One B-rep face of a CAD part: STEP entity #131.
In plain terms, the planar face has unit normal (0, 0, 1).
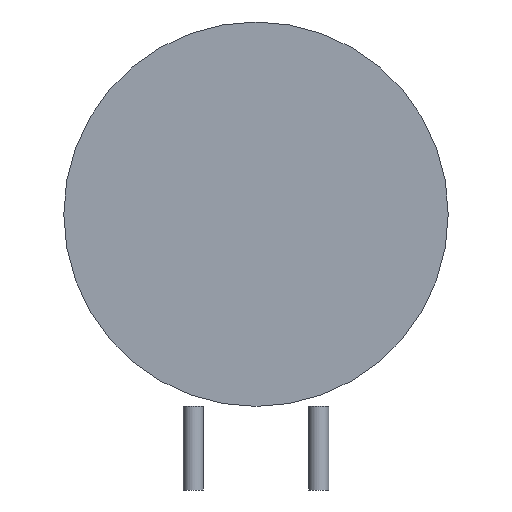
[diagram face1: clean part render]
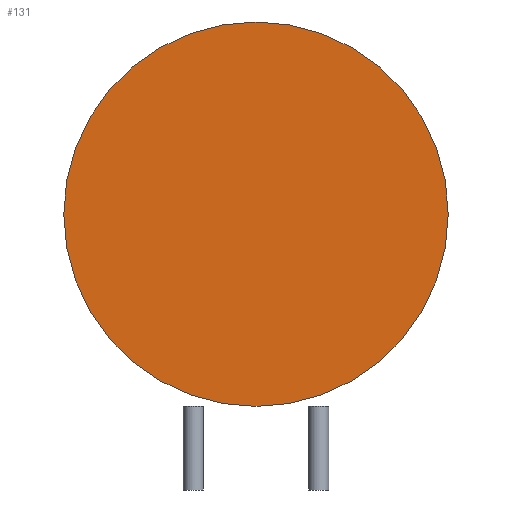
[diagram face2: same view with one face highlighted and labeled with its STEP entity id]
Its self-contained STEP definition (entity closure, numbers rounded to 3 decimals):
#47 = EDGE_CURVE('',#48,#48,#50,.T.);
#48 = VERTEX_POINT('',#49);
#49 = CARTESIAN_POINT('',(11.5,0.,9.));
#50 = SURFACE_CURVE('',#51,(#56,#68),.PCURVE_S1.);
#51 = CIRCLE('',#52,11.5);
#52 = AXIS2_PLACEMENT_3D('',#53,#54,#55);
#53 = CARTESIAN_POINT('',(0.,0.,9.));
#54 = DIRECTION('',(0.,0.,1.));
#55 = DIRECTION('',(1.,0.,-0.));
#56 = PCURVE('',#57,#62);
#57 = CYLINDRICAL_SURFACE('',#58,11.5);
#58 = AXIS2_PLACEMENT_3D('',#59,#60,#61);
#59 = CARTESIAN_POINT('',(0.,0.,0.));
#60 = DIRECTION('',(0.,0.,1.));
#61 = DIRECTION('',(1.,0.,-0.));
#62 = DEFINITIONAL_REPRESENTATION('',(#63),#67);
#63 = LINE('',#64,#65);
#64 = CARTESIAN_POINT('',(0.,9.));
#65 = VECTOR('',#66,1.);
#66 = DIRECTION('',(1.,0.));
#67 = ( GEOMETRIC_REPRESENTATION_CONTEXT(2) 
PARAMETRIC_REPRESENTATION_CONTEXT() REPRESENTATION_CONTEXT('2D SPACE',''
  ) );
#68 = PCURVE('',#69,#74);
#69 = PLANE('',#70);
#70 = AXIS2_PLACEMENT_3D('',#71,#72,#73);
#71 = CARTESIAN_POINT('',(0.,0.,9.));
#72 = DIRECTION('',(0.,0.,1.));
#73 = DIRECTION('',(1.,0.,-0.));
#74 = DEFINITIONAL_REPRESENTATION('',(#75),#79);
#75 = CIRCLE('',#76,11.5);
#76 = AXIS2_PLACEMENT_2D('',#77,#78);
#77 = CARTESIAN_POINT('',(0.,0.));
#78 = DIRECTION('',(1.,0.));
#79 = ( GEOMETRIC_REPRESENTATION_CONTEXT(2) 
PARAMETRIC_REPRESENTATION_CONTEXT() REPRESENTATION_CONTEXT('2D SPACE',''
  ) );
#131 = ADVANCED_FACE('',(#132),#69,.T.);
#132 = FACE_BOUND('',#133,.T.);
#133 = EDGE_LOOP('',(#134));
#134 = ORIENTED_EDGE('',*,*,#47,.T.);
